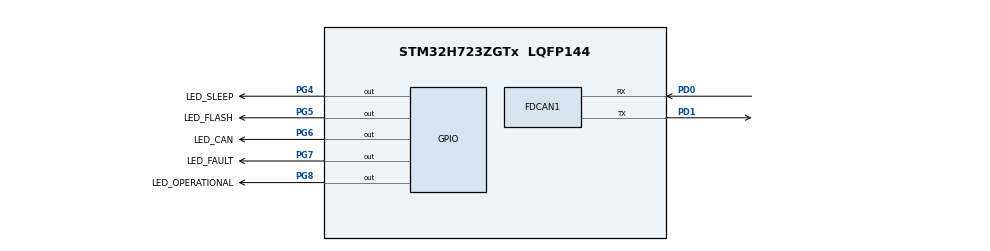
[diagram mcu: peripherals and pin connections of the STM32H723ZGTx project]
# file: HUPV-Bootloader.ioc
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FDCAN1.AutoRetransmission=ENABLE
FDCAN1.CalculateBaudRateNominal=749999
FDCAN1.CalculateTimeBitNominal=1333
FDCAN1.CalculateTimeQuantumNominal=16.666666666666668
FDCAN1.DataSyncJumpWidth=4
FDCAN1.DataTimeSeg1=14
FDCAN1.DataTimeSeg2=5
FDCAN1.FrameFormat=FDCAN_FRAME_FD_BRS
FDCAN1.Mode=FDCAN_MODE_NORMAL
FDCAN1.NominalPrescaler=1
FDCAN1.NominalSyncJumpWidth=16
FDCAN1.NominalTimeSeg1=59
FDCAN1.NominalTimeSeg2=20
FDCAN1.RxBufferSize=FDCAN_DATA_BYTES_64
FDCAN1.RxFifo0ElmtSize=FDCAN_DATA_BYTES_64
FDCAN1.RxFifo0ElmtsNbr=16
FDCAN1.RxFifo1ElmtSize=FDCAN_DATA_BYTES_64
FDCAN1.StdFiltersNbr=1
FDCAN1.TxElmtSize=FDCAN_DATA_BYTES_64
FDCAN1.TxFifoQueueElmtsNbr=16
Mcu.Family=STM32H7
Mcu.Name=STM32H723ZGTx
Mcu.Package=LQFP144
NVIC.PriorityGroup=NVIC_PRIORITYGROUP_4
PA13(JTMS/SWDIO).GPIO_Label=SWDIO
PA13(JTMS/SWDIO).Mode=JTAG_4_pins
PA13(JTMS/SWDIO).Signal=DEBUG_JTMS-SWDIO
PA14(JTCK/SWCLK).GPIO_Label=SWCLK
PA14(JTCK/SWCLK).Mode=JTAG_4_pins
PA14(JTCK/SWCLK).Signal=DEBUG_JTCK-SWCLK
PA15(JTDI).Mode=JTAG_4_pins
PA15(JTDI).Signal=DEBUG_JTDI
PB3(JTDO/TRACESWO).GPIO_Label=SWO
PB3(JTDO/TRACESWO).Mode=JTAG_4_pins
PB3(JTDO/TRACESWO).Signal=DEBUG_JTDO-SWO
PC14-OSC32_IN.Mode=LSE-External-Oscillator
PC14-OSC32_IN.Signal=RCC_OSC32_IN
PC15-OSC32_OUT.Mode=LSE-External-Oscillator
PC15-OSC32_OUT.Signal=RCC_OSC32_OUT
PD0.Mode=FDCAN_Activate
PD0.Signal=FDCAN1_RX
PD1.Mode=FDCAN_Activate
PD1.Signal=FDCAN1_TX
PG4.GPIO_Label=LED_SLEEP
PG4.Signal=GPIO_Output
PG5.GPIO_Label=LED_FLASH
PG5.Signal=GPIO_Output
PG6.GPIO_Label=LED_CAN
PG6.Signal=GPIO_Output
PG7.GPIO_Label=LED_FAULT
PG7.Signal=GPIO_Output
PG8.GPIO_Label=LED_OPERATIONAL
PG8.Signal=GPIO_Output
PH0-OSC_IN.GPIO_Label=MCO
PH0-OSC_IN.Mode=HSE-External-Oscillator
PH0-OSC_IN.Signal=RCC_OSC_IN
PH1-OSC_OUT.Mode=HSE-External-Oscillator
PH1-OSC_OUT.Signal=RCC_OSC_OUT
ProjectManager.HeapSize=0x200
ProjectManager.StackSize=0x400
ProjectManager.TargetToolchain=STM32CubeIDE
RCC.ADCFreq_Value=150000000
RCC.APB1Freq_Value=137500000
RCC.APB2Freq_Value=137500000
RCC.APB3Freq_Value=137500000
RCC.APB4Freq_Value=137500000
RCC.CortexFreq_Value=550000000
RCC.D1PPRE=RCC_APB3_DIV2
RCC.D2PPRE1=RCC_APB1_DIV2
RCC.D2PPRE2=RCC_APB2_DIV2
RCC.D3PPRE=RCC_APB4_DIV2
RCC.DIVM1=4
RCC.DIVM2=8
RCC.DIVN1=275
RCC.DIVN2=300
RCC.DIVP1=1
RCC.DIVQ1=4
RCC.DIVQ2=5
RCC.FDCANCLockSelection=RCC_FDCANCLKSOURCE_PLL2
RCC.HCLKFreq_Value=275000000
RCC.HPRE=RCC_HCLK_DIV2
RCC.HSE_VALUE=8000000
RCC.PLLFRACN=0
RCC.PLLSourceVirtual=RCC_PLLSOURCE_HSE
RCC.SYSCLKFreq_VALUE=550000000
RCC.SYSCLKSource=RCC_SYSCLKSOURCE_PLLCLK
RCC.USBCLockSelection=RCC_USBCLKSOURCE_HSI48
RCC.USBFreq_Value=48000000
TIM23.ClockDivision=TIM_CLOCKDIVISION_DIV2
TIM23.Prescaler=55000
VP_TIM23_VS_ClockSourceINT.Mode=Internal
board=NUCLEO-H723ZG

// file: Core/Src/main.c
/* USER CODE BEGIN Header */
/**
  ******************************************************************************
  * @file           : main.c
  * @brief          : Main program body
  ******************************************************************************
  * @attention
  *
  * Copyright (c) 2023 STMicroelectronics.
  * All rights reserved.
  *
  * This software is licensed under terms that can be found in the LICENSE file
  * in the root directory of this software component.
  * If no LICENSE file comes with this software, it is provided AS-IS.
  *
  ******************************************************************************
  */
/* USER CODE END Header */
#include "main.h"

/* USER CODE BEGIN Includes */
#include "../App/Bootloader.h"
#include "../Tests/flash_test.h"
/* USER CODE END Includes */

FDCAN_HandleTypeDef hfdcan1;

TIM_HandleTypeDef htim23;

void SystemClock_Config(void);
static void MX_GPIO_Init(void);
static void MX_FDCAN1_Init(void);
static void MX_TIM23_Init(void);

int main(void)
{

  /* MCU Configuration--------------------------------------------------------*/

  /* Reset of all peripherals, Initializes the Flash interface and the Systick. */
  HAL_Init();

  /* Configure the system clock */
  SystemClock_Config();

  /* Initialize all configured peripherals */
  MX_GPIO_Init();
  MX_FDCAN1_Init();
  MX_TIM23_Init();
  /* USER CODE BEGIN 2 */
  HAL_TIM_Base_Start(&htim23);
  HAL_FDCAN_Start(&hfdcan1);
  HAL_FDCAN_ActivateNotification(&hfdcan1, FDCAN_IT_RX_FIFO0_NEW_MESSAGE, 0);

  bootloader_start();
  /* USER CODE END 2 */

  /* Infinite loop */
  while (1)
  {

  }
}

void SystemClock_Config(void)
{
  RCC_OscInitTypeDef RCC_OscInitStruct = {0};
  RCC_ClkInitTypeDef RCC_ClkInitStruct = {0};

  /** Supply configuration update enable
  */
  HAL_PWREx_ConfigSupply(PWR_LDO_SUPPLY);

  /** Configure the main internal regulator output voltage
  */
  __HAL_PWR_VOLTAGESCALING_CONFIG(PWR_REGULATOR_VOLTAGE_SCALE0);

  while(!__HAL_PWR_GET_FLAG(PWR_FLAG_VOSRDY)) {}

  /** Macro to configure the PLL clock source
  */
  __HAL_RCC_PLL_PLLSOURCE_CONFIG(RCC_PLLSOURCE_HSE);

  /** Initializes the RCC Oscillators according to the specified parameters
  * in the RCC_OscInitTypeDef structure.
  */
  RCC_OscInitStruct.OscillatorType = RCC_OSCILLATORTYPE_HSE;
  RCC_OscInitStruct.HSEState = RCC_HSE_ON;
  RCC_OscInitStruct.PLL.PLLState = RCC_PLL_ON;
  RCC_OscInitStruct.PLL.PLLSource = RCC_PLLSOURCE_HSE;
  RCC_OscInitStruct.PLL.PLLM = 2;
  RCC_OscInitStruct.PLL.PLLN = 44;
  RCC_OscInitStruct.PLL.PLLP = 1;
  RCC_OscInitStruct.PLL.PLLQ = 4;
  RCC_OscInitStruct.PLL.PLLR = 2;
  RCC_OscInitStruct.PLL.PLLRGE = RCC_PLL1VCIRANGE_3;
  RCC_OscInitStruct.PLL.PLLVCOSEL = RCC_PLL1VCOWIDE;
  RCC_OscInitStruct.PLL.PLLFRACN = 0;
  if (HAL_RCC_OscConfig(&RCC_OscInitStruct) != HAL_OK)
  {
    Error_Handler();
  }

  /** Initializes the CPU, AHB and APB buses clocks
  */
  RCC_ClkInitStruct.ClockType = RCC_CLOCKTYPE_HCLK|RCC_CLOCKTYPE_SYSCLK
                              |RCC_CLOCKTYPE_PCLK1|RCC_CLOCKTYPE_PCLK2
                              |RCC_CLOCKTYPE_D3PCLK1|RCC_CLOCKTYPE_D1PCLK1;
  RCC_ClkInitStruct.SYSCLKSource = RCC_SYSCLKSOURCE_PLLCLK;
  RCC_ClkInitStruct.SYSCLKDivider = RCC_SYSCLK_DIV1;
  RCC_ClkInitStruct.AHBCLKDivider = RCC_HCLK_DIV2;
  RCC_ClkInitStruct.APB3CLKDivider = RCC_APB3_DIV2;
  RCC_ClkInitStruct.APB1CLKDivider = RCC_APB1_DIV2;
  RCC_ClkInitStruct.APB2CLKDivider = RCC_APB2_DIV2;
  RCC_ClkInitStruct.APB4CLKDivider = RCC_APB4_DIV2;

  if (HAL_RCC_ClockConfig(&RCC_ClkInitStruct, FLASH_LATENCY_3) != HAL_OK)
  {
    Error_Handler();
  }
}

static void MX_FDCAN1_Init(void)
{

	  hfdcan1.Instance = FDCAN1;
	  hfdcan1.Init.FrameFormat = FDCAN_FRAME_FD_NO_BRS;
	  hfdcan1.Init.Mode = FDCAN_MODE_NORMAL;
	  hfdcan1.Init.AutoRetransmission = DISABLE;
	  hfdcan1.Init.TransmitPause = DISABLE;
	  hfdcan1.Init.ProtocolException = DISABLE;
	  hfdcan1.Init.NominalPrescaler = 1;
	  hfdcan1.Init.NominalSyncJumpWidth = 4;
	  hfdcan1.Init.NominalTimeSeg1 = 15;
	  hfdcan1.Init.NominalTimeSeg2 = 4;
	  hfdcan1.Init.DataPrescaler = 11;
	  hfdcan1.Init.DataSyncJumpWidth = 4;
	  hfdcan1.Init.DataTimeSeg1 = 17;
	  hfdcan1.Init.DataTimeSeg2 = 8;
	  hfdcan1.Init.MessageRAMOffset = 0;
	  hfdcan1.Init.StdFiltersNbr = 0;
	  hfdcan1.Init.ExtFiltersNbr = 0;
	  hfdcan1.Init.RxFifo0ElmtsNbr = 16;
	  hfdcan1.Init.RxFifo0ElmtSize = FDCAN_DATA_BYTES_64;
	  hfdcan1.Init.RxFifo1ElmtsNbr = 0;
	  hfdcan1.Init.RxFifo1ElmtSize = FDCAN_DATA_BYTES_64;
	  hfdcan1.Init.RxBuffersNbr = 0;
	  hfdcan1.Init.RxBufferSize = FDCAN_DATA_BYTES_64;
	  hfdcan1.Init.TxEventsNbr = 0;
	  hfdcan1.Init.TxBuffersNbr = 0;
	  hfdcan1.Init.TxFifoQueueElmtsNbr = 16;
	  hfdcan1.Init.TxFifoQueueMode = FDCAN_TX_FIFO_OPERATION;
	  hfdcan1.Init.TxElmtSize = FDCAN_DATA_BYTES_64;
  if (HAL_FDCAN_Init(&hfdcan1) != HAL_OK)
  {
    Error_Handler();
  }

}

static void MX_TIM23_Init(void)
{

  TIM_ClockConfigTypeDef sClockSourceConfig = {0};
  TIM_MasterConfigTypeDef sMasterConfig = {0};

  htim23.Instance = TIM23;
  htim23.Init.Prescaler = 55000;
  htim23.Init.CounterMode = TIM_COUNTERMODE_UP;
  htim23.Init.Period = 4294967295;
  htim23.Init.ClockDivision = TIM_CLOCKDIVISION_DIV2;
  htim23.Init.AutoReloadPreload = TIM_AUTORELOAD_PRELOAD_DISABLE;
  if (HAL_TIM_Base_Init(&htim23) != HAL_OK)
  {
    Error_Handler();
  }
  sClockSourceConfig.ClockSource = TIM_CLOCKSOURCE_INTERNAL;
  if (HAL_TIM_ConfigClockSource(&htim23, &sClockSourceConfig) != HAL_OK)
  {
    Error_Handler();
  }
  sMasterConfig.MasterOutputTrigger = TIM_TRGO_RESET;
  sMasterConfig.MasterSlaveMode = TIM_MASTERSLAVEMODE_DISABLE;
  if (HAL_TIMEx_MasterConfigSynchronization(&htim23, &sMasterConfig) != HAL_OK)
  {
    Error_Handler();
  }

}

static void MX_GPIO_Init(void)
{
  GPIO_InitTypeDef GPIO_InitStruct = {0};

  /* GPIO Ports Clock Enable */
  __HAL_RCC_GPIOC_CLK_ENABLE();
  __HAL_RCC_GPIOH_CLK_ENABLE();
  __HAL_RCC_GPIOG_CLK_ENABLE();
  __HAL_RCC_GPIOA_CLK_ENABLE();
  __HAL_RCC_GPIOD_CLK_ENABLE();
  __HAL_RCC_GPIOB_CLK_ENABLE();

  /*Configure GPIO pin Output Level */
  HAL_GPIO_WritePin(GPIOG, LED_SLEEP_Pin|LED_FLASH_Pin|LED_CAN_Pin|LED_FAULT_Pin
                          |LED_OPERATIONAL_Pin, GPIO_PIN_RESET);

  /*Configure GPIO pins : LED_SLEEP_Pin LED_FLASH_Pin LED_CAN_Pin LED_FAULT_Pin
                           LED_OPERATIONAL_Pin */
  GPIO_InitStruct.Pin = LED_SLEEP_Pin|LED_FLASH_Pin|LED_CAN_Pin|LED_FAULT_Pin
                          |LED_OPERATIONAL_Pin;
  GPIO_InitStruct.Mode = GPIO_MODE_OUTPUT_PP;
  GPIO_InitStruct.Pull = GPIO_NOPULL;
  GPIO_InitStruct.Speed = GPIO_SPEED_FREQ_LOW;
  HAL_GPIO_Init(GPIOG, &GPIO_InitStruct);

}

void Error_Handler(void)
{
  /* USER CODE BEGIN Error_Handler_Debug */
  /* User can add his own implementation to report the HAL error return state */
  __disable_irq();
  while (1)
  {
	  HAL_GPIO_TogglePin(LED_FAULT_GPIO_Port, LED_FAULT_Pin);
	  uint32_t i;
	  for (i = 0; i < 10000000; ++i) {
		  __NOP();
	  }
  }
  /* USER CODE END Error_Handler_Debug */
}
